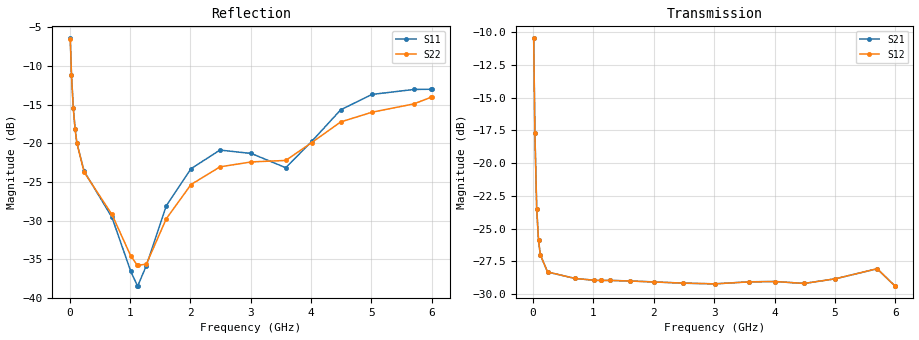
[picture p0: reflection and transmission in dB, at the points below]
! Integrated Device Technology
! Corporate Headquarters
! 6024 Silver Creek Valley Road
! San Jose, CA 95138  USA
! Phone:  1-408-284-8200
! Toll Free:  1-800-223-1366
! Webpage:  http://www.idt.com/
! Timing and RF Division
! 515 Groton Road, Suite 102
! Westford, MA 01886-6024
! Device:  F1951
! Description: 6-bit 0.5 dB Digital Step Attenuator
! Frequency:  100.0 -  4000.00 MHz
! Package:  4x4 mm Thin QFN Plastic Package: 24 pin
! Ports:  2 RF, 6 DC
!  Pin  1  = NC
!  Pin  2  = RF1  =  Port 1
!  Pin  3  = GND
!  Pin  4  = NC
!  Pin  5  = Serial Data Out (SDO)
!  Pin  6  = NC
!  Pin  7  = Reset Bar ( RSTb)
!  Pin  8  = Clock (CLK)
!  Pin  9  = Chip Select Bar (CSb)
!  Pin 10  = NC
!  Pin 11  = Serial Data In (SDI)
!  Pin 12  = NC
!  Pin 13  = NC
!  Pin 14  = VDD
!  Pin 15  = NC
!  Pin 16  = GND
!  Pin 17  = RF2  =  Port 2
!  Pin 18  = NC
!  Pin 19  = GND
!  Pin 20  = GND
!  Pin 21  = GND
!  Pin 22  = GND
!  Pin 23  = GND
!  Pin 24  = GND
! State:  56
! Atten State:  28.0 dB
! Voltage:  +3.30 Volts
! Current:  0.477 mA
! Data:  The device was measured on a F195X evaluation board which has
!  individual transmission lines to the RF pins.  Data was collected
!  de-embedded using a Automatic Fixture Removal [AFR] (Keysight Technologies).
!  The reference plane is the edge of the package pin.
! Misc:  Lot Code  1225BCA
!  Action Tracker AT0399
! Date Measured:  2018-09-13
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# GHz S dB R 50
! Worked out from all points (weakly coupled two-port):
!   600 points, 10 MHz to 6 GHz, reference 50 ohm
!   highest |S21| = -10.46 dB at 10 MHz (marker M1); lowest = -29.4 dB at 5.99 GHz (marker M2)
!   lowest |S11| = -38.4 dB at 1.13 GHz (marker M3), VSWR 1.02, Z = 48.8 + j0.223 ohm
!   |S11| at or under -10 dB: 24.67 MHz to end of sweep
!   |S22| runs from -36.2 to -6.5 dB; largest |S21 - S12| = 0.00014
!   S11 on the Smith chart (normalised r, x): 10 MHz: 1.76, -1.22; 30 MHz: 1.11, -0.60; 60 MHz: 0.98, -0.34; 1.12 GHz: 0.98, +0.00; 6 GHz: 0.81, +0.36
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0.01  -6.43 -34.2  -10.46 -39.8  -10.46 -39.8  -6.48 -34.2
0.03  -11.11 -63.4  -17.70 -62.9  -17.70 -62.9  -11.16 -63.4
0.06  -15.39 -83.1  -23.49 -56.0  -23.49 -56.0  -15.47 -83.2
0.09  -18.12 -95.0  -25.89 -45.2  -25.89 -45.2  -18.18 -95.2
0.12  -19.98 -103.8  -27.01 -37.2  -27.01 -37.2  -20.01 -103.7
0.24  -23.62 -122.9  -28.33 -22.4  -28.32 -22.3  -23.74 -122.9
0.7  -29.57 -136.4  -28.82 -14.9  -28.82 -14.9  -29.21 -138.7
1.01  -36.52 -158.0  -28.95 -16.1  -28.95 -16.1  -34.54 -153.8
1.12  -38.40 172.5  -28.97 -16.6  -28.97 -16.6  -35.77 -169.4
1.13  -38.42 169.0  -28.97 -16.6  -28.96 -16.6  -35.78 -170.9
1.27  -35.83 131.5  -28.96 -17.6  -28.97 -17.6  -35.64 162.8
1.6  -28.09 115.1  -29.01 -20.4  -29.01 -20.4  -29.77 134.3
2.01  -23.29 123.0  -29.08 -24.2  -29.09 -24.2  -25.34 135.0
2.49  -20.88 135.8  -29.18 -28.6  -29.17 -28.6  -23.05 142.1
3.01  -21.32 145.7  -29.23 -33.0  -29.23 -32.9  -22.41 145.6
3.58  -23.16 124.5  -29.07 -37.8  -29.08 -37.8  -22.22 128.7
4.01  -19.76 100.4  -29.05 -41.7  -29.05 -41.6  -19.91 116.5
4.49  -15.67 98.8  -29.20 -45.3  -29.20 -45.3  -17.24 114.6
5.01  -13.68 107.7  -28.84 -47.0  -28.84 -46.9  -15.98 117.1
5.7  -13.04 112.6  -28.08 -58.3  -28.07 -58.3  -14.91 109.9
5.99  -13.01 106.7  -29.37 -60.0  -29.37 -60.0  -14.04 106.2
6  -13.00 106.4  -29.37 -59.5  -29.36 -59.4  -14.00 106.1
